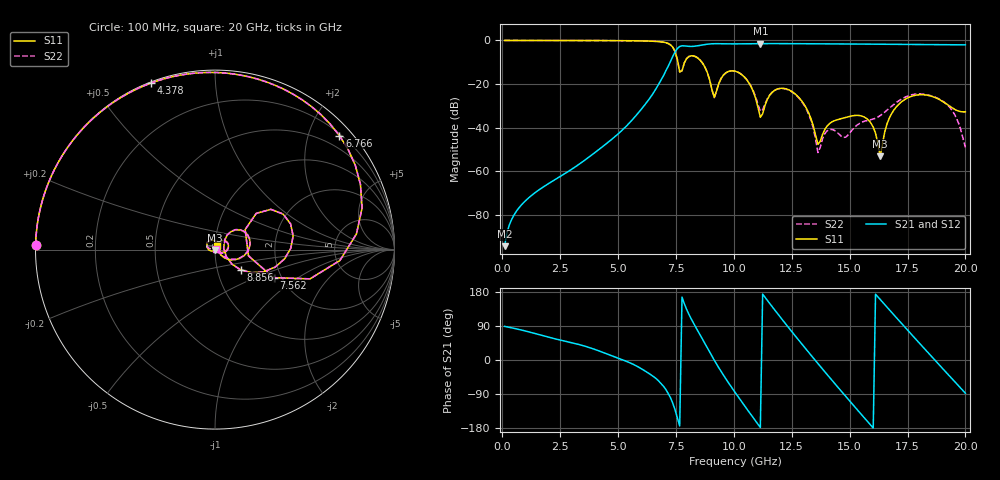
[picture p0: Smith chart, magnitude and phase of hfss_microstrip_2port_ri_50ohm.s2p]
! Touchstone file exported from HFSS 2025.2.0
!  File:  C:/hfss/touchstone_fixtures.aedt
!  Generated:  12:37:07 AM Aug 26, 2026
!  Design:  microstrip
!  Project:  touchstone_fixtures
!  Setup:  Setup1
!  Solution:  Sweep
# GHz S RI R 50.000000
! Terminal data exported
! Port[1] = 1
! Port[2] = 2
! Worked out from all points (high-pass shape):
!   201 points, 100 MHz to 20 GHz, reference 50 ohm
!   highest |S21| = -1.41 dB at 11.14 GHz (marker M1); lowest = -94.4 dB at 100 MHz (marker M2)
!   |S21| within 3 dB of the highest: 7.516 GHz to end of sweep
!   lowest |S11| = -53.2 dB at 16.32 GHz (marker M3), VSWR 1.00, Z = 50.2 - j0.139 ohm
!   |S11| at or under -10 dB: 7.583 GHz to 7.876 GHz (292.3 MHz wide, 3.78 % of centre); 8.619 GHz to end of sweep
!   |S22| runs from -51.4 to 0.0 dB; largest |S21 - S12| = 9e-15
!   S11 on the Smith chart (normalised r, x): 100 MHz: 0.00, +0.01; 4.378 GHz: 0.00, +0.69; 6.766 GHz: 0.23, +2.55; 7.562 GHz: 1.82, -0.65; 8.856 GHz: 1.30, -0.30; 20 GHz: 1.02, +0.04
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0.1  -0.9996 0.0248  4.45e-07 1.91e-05  4.45e-07 1.91e-05  -0.9996 0.0248
! Gamma 314.274619904661 -0.14406393139023 314.275157690951 -0.144553584415669
! Port Impedance 50 0 50 0
3.483  -0.6052 0.7926  0.00132 0.00103  0.00132 0.00103  -0.6054 0.7924
4.3785  -0.3566 0.9279  0.00362 0.00127  0.00362 0.00127  -0.3568 0.9278
6.7665  0.693 0.6357  0.0567 -0.0848  0.0567 -0.0848  0.6929 0.6358
7.5625  0.3261 -0.1564  -0.5818 -0.3028  -0.5818 -0.3028  0.3263 -0.1563
8.1595  0.4213 0.1436  -0.2316 0.6923  -0.2316 0.6923  0.4213 0.1433
8.856  0.1436 -0.1129  0.6984 0.4324  0.6984 0.4324  0.143 -0.1132
9.1545  0.0493 0.00572  0.8429 -0.00587  0.8429 -0.00587  0.0483 0.00587
10.05  0.1952 0.0299  0.071 -0.8315  0.071 -0.8315  0.1952 0.0329
11.1445  0.0173 -0.0014  -0.8497 -0.0293  -0.8497 -0.0293  0.0237 -0.00147
12.239  0.0748 0.0221  -0.0754 0.8405  -0.0754 0.8405  0.0755 0.0145
13.433  0.0091 -0.00585  0.8359 0.0764  0.8359 0.0764  0.0064 -0.00716
13.632  0.00405 0.000917  0.8269 -0.1373  0.8269 -0.1373  0.00269 -6.17e-05
14.03  0.00142 0.0108  0.6544 -0.5199  0.6544 -0.5199  0.00265 0.00803
14.826  0.000797 0.0171  -0.0813 -0.8264  -0.0813 -0.8264  -0.00207 0.00568
15.821  0.00723 0.0129  -0.7976 -0.2044  -0.7976 -0.2044  -0.0123 0.00826
16.3185  0.0017 -0.00138  -0.7697 0.2822  -0.7697 0.2822  -0.018 0.00561
16.7165  -0.0145 -0.00817  -0.5514 0.6024  -0.5514 0.6024  -0.0275 0.00522
17.5125  -0.0448 0.018  0.1652 0.7932  0.1652 0.7932  -0.0456 0.0274
18.5075  -0.00997 0.0522  0.7873 0.1583  0.7873 0.1583  -0.0145 0.052
19.403  0.0115 0.0267  0.5315 -0.5943  0.5315 -0.5943  0.00778 0.0247
20  0.011 0.0203  0.033 -0.7922  0.033 -0.7922  0.00284 0.00211
